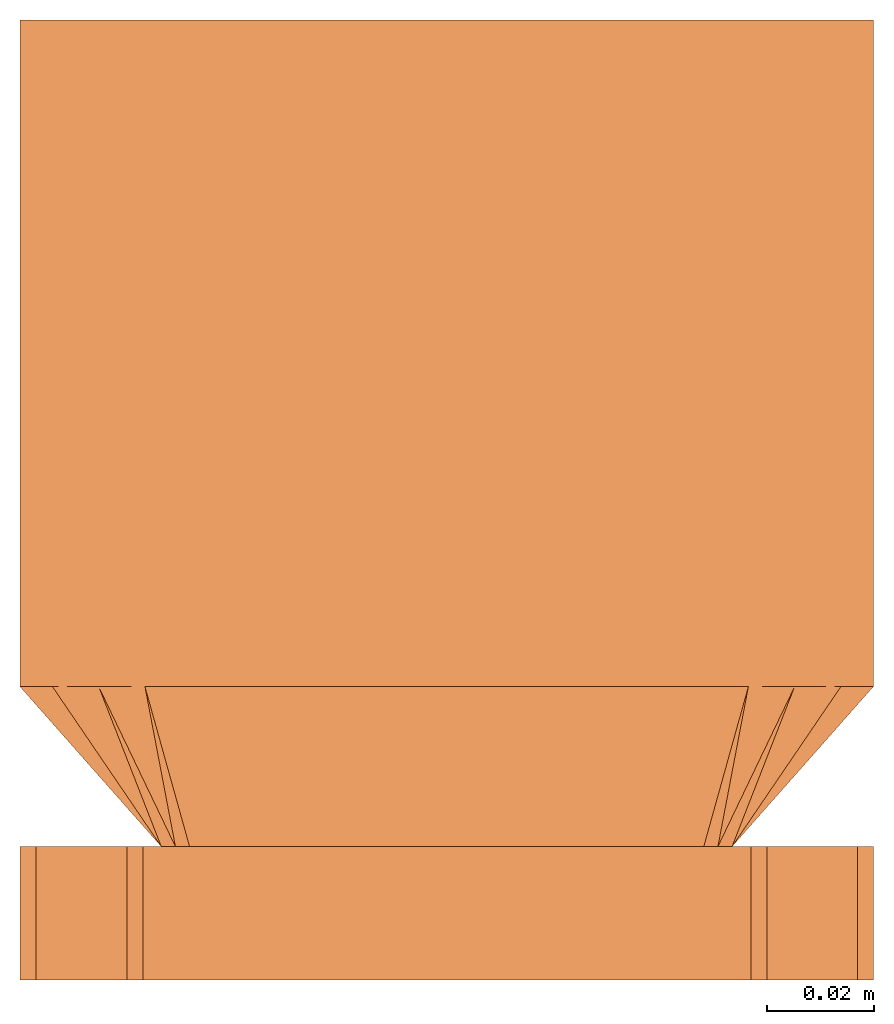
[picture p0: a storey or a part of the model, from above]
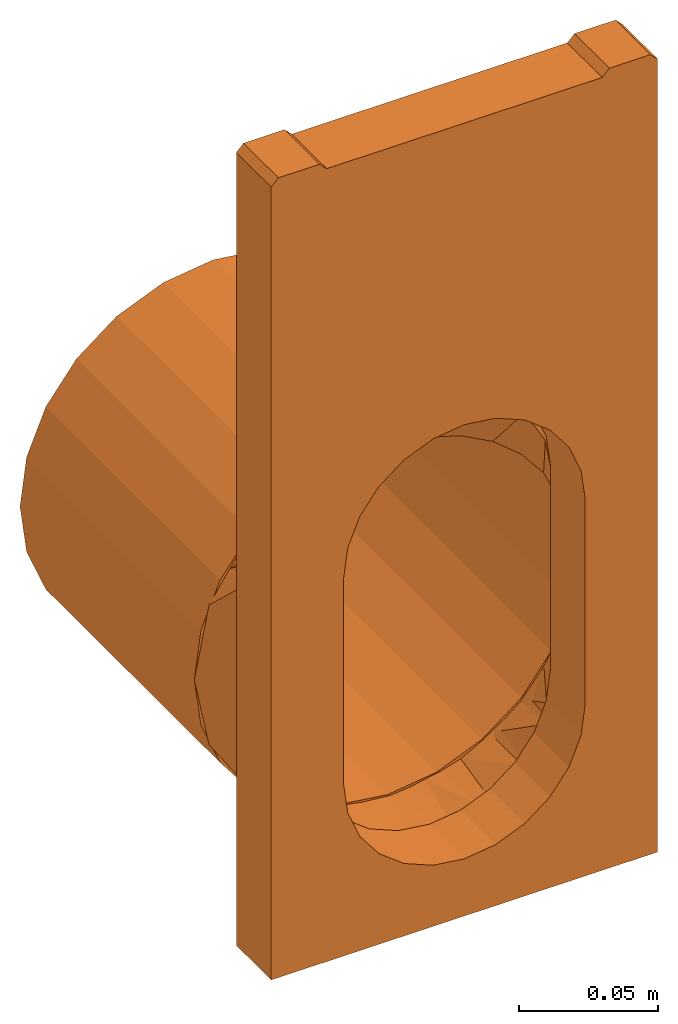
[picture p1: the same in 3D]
Properties of the parts of a building model (IFC2X3)

# File
Description: ViewDefinition [CoordinationView]
File name: 32308 - Junction end cap.ifc
Time: 2013-09-18T17:35:14
Written by: Autodesk Revit 2013
Made in: 20120221_2030(x64)

# IfcProject, Project Number
LongName: Project Name; Phase: Project Status

# IfcSite, Default
RefLatitude: 42, 21, 30, 344238; RefLongitude: -71, -3, -35, -194702; RefElevation: 0 mm

# IfcBuilding
Pset_BuildingCommon - NumberOfStoreys: 2
Other - Project Issue Date: Issue Date; Project Status: Project Status; Project Number: Project Number; Project Name: Project Name; Client Name: Owner; Project Address: Enter address here

# IfcBuildingStorey (2)
Constraints - Elevation Base: 0
Graphics - Symbol: M_Level Head - Circle: M_Level Head - Circle; Line Pattern: Center; Symbol at End 1 Default: no; Symbol at End 2 Default: yes; Color: 0; Line Weight: 1
Identity Data - Structural: no; Building Story: yes
Dimensions - Computation Height: 0 mm
Name | LongName = Name | Elevation (mm) = Constraints, Elevation (mm)
T.O. Fnd. Wall | T.O. Fnd. Wall | -300
Level 1 | Level 1 | 0

# IfcBuildingElementProxy: 32308 - Junction end cap, Civil-Drainage-Channel-ACO-KerbDrain-HB480(amar):32308 - Junction end cap:32308 - Junction end cap:481515
In: T.O. Fnd. Wall
Material: Acetal Resin, Black
Other - Revision: 1; CreatedBy: www.aco.co.uk
Data - Drainage Slot Width: N/A; Invert Depth: N/A; Concrete Surround Volume - Load Class A 15 - D 400 - Grass or Asphalt Pavement: N/A; Load Class: N/A; Installation - Concrete Grade: N/A; Product Standard: N/A; Concrete Surround Volume - Load Class A 15 - D 400 - Concrete Pavement: N/A; Product Dimensions: 50mm x 150mm x 480mm (LxWxH); Connection Pipe O.D: Ø160mm; Channel C.S.A: N/A; Product Weight: 2.1 Kg; ACO Hydraulic Design Software: N/A; Drainage Slot Intake area: N/A; Hydraulic Performance: N/A
Phasing - Phase Created: Phase 1
Constraints - Level: Level: Level 1; Moves With Nearby Elements: no
Dimensions - Volume: 1130681 mm3; Void Depth: -350 mm; Mitre Void Start: 2465 mm; Mitre Void End: 2470 mm; junction void depth: 331.995 mm; Void End I/O: 2 mm; Void Width: 160 mm; Void Length: 25 mm; Junction Start: -5 mm; Void Start I/O: 0 mm; Mitre Long end: 500 mm; Mitre Small End: 487 mm; Straight Void Start: 0 mm; I/O endcap void depth: 2000 mm; Junction End: 155 mm
Pset_BuildingElementProxyCommon - Reference: 32308 - Junction end cap
Construction - RH inlet/outlet end cap: no; LH inlet/outlet end cap: no; Bus stop kerb: no; 25-11m external mitre: no; RH drop kerb: no; Closing end cap: no; LH drop kerb: no; LH BS transition kerb: no; Junction access unit: no; Access Unit: no; Junction channel: no; RH BS transition kerb: no; KDHB480 500_blindunit: no; perforated centre stone: no; 7-6m external mitre: no; Junction end cap: yes; HB480-500: no; 25-11m internal mitre: no; Centre Stone: no; cable loop: no; 10-8m external mitre: no
Materials and Finishes - End Cap Material: Vienite® Synthetic Resin Concrete; Connection Pipe Material Colour: Black; Access Cover/Frame Colour: N/A; Access Cover/Frame Finish: N/A; Connection Pipe Material: Medium Density Polyethylene; End Cap Colour: Black; Channel Material: N/A; Channel Colour: N/A; Access Cover/Frame Material: N/A
Identity Data - Type Comments: ACO KerbDrain HB480 half battered junction channel inlet/outlet end cap; Model: ACO KerbDrain HB480; Model Description: Combined kerb and drainage system; Assembly Code: D2040; Product Code: 32308; Installation guidelines: http://www.aco.co.uk/download.php?id=120; OmniClass Number: 23.70.50.24; Product Page URL: http://www.aco.co.uk/product_detail.php?id=3; Maintenance guidelines: http://www.aco.co.uk/download.php?id=120; OmniClass Title: Rainwater Removal; Address: ACO Business Park, Hitchin Road, Shefford, Bedfordshire, United Kingdom SG17 5TE; e-mail Technical: technical@aco.co.uk; Cost: 0; URL: www.aco.co.uk; e-mail Sales: customersupport@aco.co.uk; Telephone: +44 (0)1462 816666; Assembly Description: Rain Water Drainage; Product brochure: http://www.aco.co.uk/download.php?id=120; Manufacturer: ACO Technologies plc - ACO Water Management Division; Price: POA - contact ACO; Fax: +44 (0)1462 815895
Green Building Properties - Access Cover/Frame Recycled Material Content: N/A; Channel Recycled Material Content: N/A; End Cap Recycled Material Content: 20% minimum; Access Cover/Frame Recyclable: N/A; End Cap Recyclable: Fully recyclable; Channel Recyclable: N/A
General - TagNumber: 0.000000; SerialNumber: 0.000000

# IfcOpeningElement: Opening (3)
In: Level 1
Structural - Structural: no; Enable Analytical Model: no
Constraints - Related to Mass: no; Room Bounding: yes; Height Offset From Level: 0 mm; Level: Level: Level 1
Phasing - Phase Created: Phase 1
Dimensions - Perimeter: 9790 mm; Area: 5901750 mm2; Volume: 2355234079 mm3; Thickness: 400 mm
Analytical Properties - Thermal mass: 543920; Absorptance: 0.1; Roughness: 1; Heat Transfer Coefficient (U): 2.0925; Thermal Resistance (R): 0.477897
Graphics - Coarse Scale Fill Color: 0
Construction - Function: 0; Default Thickness: 400 mm
Materials and Finishes - Structural Material: Earth

# IfcSlab: Floor:Generic Floor - 400mm, Floor:Generic Floor - 400mm:136426
In: Level 1
PredefinedType: FLOOR; Material: Earth 400 mm
Structural - Structural: no; Enable Analytical Model: no
Constraints - Related to Mass: no; Room Bounding: yes; Height Offset From Level: 0 mm; Level: Level: Level 1
Phasing - Phase Created: Phase 1
Dimensions - Perimeter: 9790 mm; Area: 5901750 mm2; Volume: 2355234079 mm3; Thickness: 400 mm
Pset_SlabCommon - Reference: Generic Floor - 400mm; IsExternal: no; LoadBearing: yes
Analytical Properties - Thermal mass: 543920; Absorptance: 0.1; Roughness: 1; Heat Transfer Coefficient (U): 2.0925; Thermal Resistance (R): 0.477897
Graphics - Coarse Scale Fill Color: 0
Construction - Function: 0; Default Thickness: 400 mm
Materials and Finishes - Structural Material: Earth
